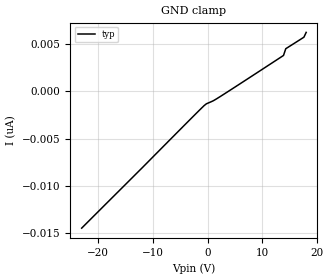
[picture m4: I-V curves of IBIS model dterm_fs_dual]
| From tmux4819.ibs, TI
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| dterm_fs_dual
[Model]   dterm_fs_dual
Model_type   Terminator
|   typ   min   max
C_comp   1.598234e-11   NA   NA
[Voltage Range]   18   NA   NA
[Temperature Range]   27   NA   NA
[GND Clamp Reference]   0   NA   NA
[GND Clamp]
|   Voltage   I(typ)   I(min)   I(max)
-23V      -14.53nA   NA         NA
-636.4mV  -1.503nA   NA         NA
2.263V    -551.7pA   NA         NA
13.86V    3.833nA    NA         NA
14.27V    4.55nA     NA         NA
17.59V    5.776nA    NA         NA
18V       6.288nA    NA         NA
